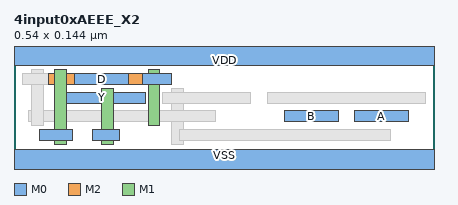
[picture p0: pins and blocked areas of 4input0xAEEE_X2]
MACRO 4input0xAEEE_X2
  CLASS CORE ;
  ORIGIN 0 0 ;
  FOREIGN 4input0xAEEE_X2 0 0 ;
  SIZE 0.5400 BY 0.1440 ;
  SYMMETRY X Y ;
  SITE coresite ;
  PIN A
    DIRECTION INPUT ;
    USE SIGNAL ;
    PORT
      LAYER M0 ;
        RECT 0.4380 0.0530 0.5070 0.0670 ;
    END
  END A
  PIN B
    DIRECTION INPUT ;
    USE SIGNAL ;
    PORT
      LAYER M0 ;
        RECT 0.3480 0.0530 0.4170 0.0670 ;
    END
  END B
  PIN C
    DIRECTION INPUT ;
    USE SIGNAL ;
    PORT
      LAYER M2 ;
        RECT 0.0450 0.1010 0.1920 0.1150 ;
      LAYER M1 ;
        RECT 0.0525 0.0240 0.0675 0.1200 ;
        RECT 0.1725 0.0480 0.1875 0.1200 ;
      LAYER M0 ;
        RECT 0.1650 0.1010 0.2025 0.1150 ;
        RECT 0.0330 0.0290 0.0750 0.0430 ;
    END
  END C
  PIN D
    DIRECTION INPUT ;
    USE SIGNAL ;
    PORT
      LAYER M0 ;
        RECT 0.0780 0.1010 0.1470 0.1150 ;
    END
  END D
  PIN Y
    DIRECTION OUTPUT ;
    USE SIGNAL ;
    PORT
      LAYER M1 ;
        RECT 0.1125 0.0240 0.1275 0.0960 ;
      LAYER M0 ;
        RECT 0.0555 0.0770 0.1695 0.0910 ;
        RECT 0.1005 0.0290 0.1350 0.0430 ;
    END
  END Y
  PIN VDD
    DIRECTION INOUT ;
    USE POWER ;
    SHAPE ABUTMENT ;
    PORT
      LAYER M0 ;
        RECT 0.0000 0.1260 0.5400 0.1620 ;
    END
  END VDD
  PIN VSS
    DIRECTION INOUT ;
    USE GROUND ;
    SHAPE ABUTMENT ;
    PORT
      LAYER M0 ;
        RECT 0.0000 -0.0180 0.5400 0.0180 ;
    END
  END VSS
  OBS
    LAYER M2 ;
      RECT 0.0180 0.0530 0.2250 0.0670 ;
    LAYER V1 ;
      RECT 0.0230 0.0530 0.0370 0.0670 ;
      RECT 0.2030 0.0530 0.2170 0.0670 ;
      RECT 0.0530 0.1010 0.0670 0.1150 ;
      RECT 0.1730 0.1010 0.1870 0.1150 ;
    LAYER M1 ;
      RECT 0.2025 0.0240 0.2175 0.0960 ;
      RECT 0.0225 0.0480 0.0375 0.1200 ;
    LAYER V0 ;
      RECT 0.0230 0.1010 0.0370 0.1150 ;
      RECT 0.2030 0.0770 0.2170 0.0910 ;
      RECT 0.1130 0.0770 0.1270 0.0910 ;
      RECT 0.1130 0.0290 0.1270 0.0430 ;
      RECT 0.0530 0.0290 0.0670 0.0430 ;
      RECT 0.1730 0.1010 0.1870 0.1150 ;
    LAYER M0 ;
      RECT 0.2130 0.0290 0.4845 0.0430 ;
      RECT 0.0555 0.0530 0.2595 0.0670 ;
      RECT 0.1905 0.0770 0.3045 0.0910 ;
      RECT 0.3255 0.0770 0.5295 0.0910 ;
      RECT 0.0105 0.1010 0.0450 0.1150 ;
  END
END 4input0xAEEE_X2
